One B-rep face of a CAD part: STEP entity #737.
In plain terms, the planar face has unit normal (-1, 0, 0).
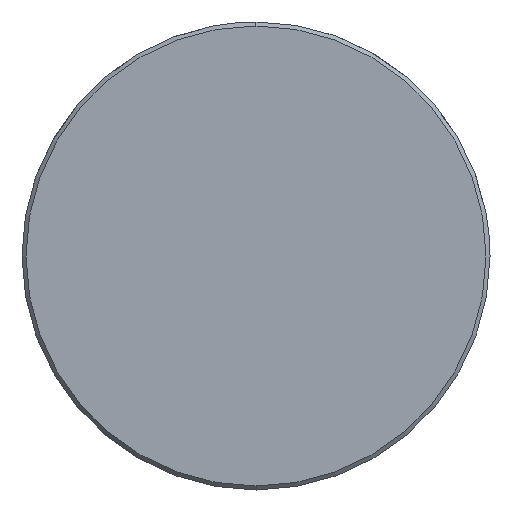
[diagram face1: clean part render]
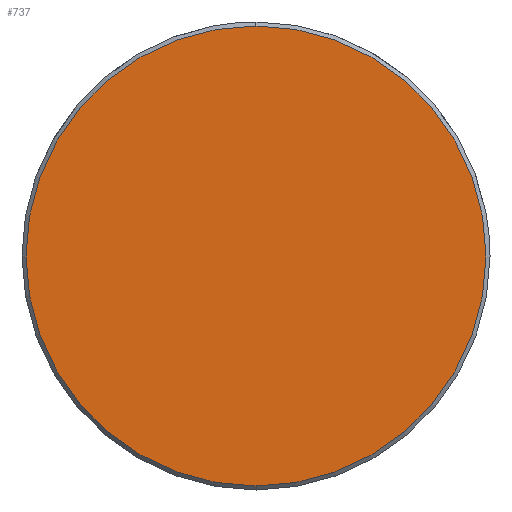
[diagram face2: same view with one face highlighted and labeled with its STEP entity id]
Its self-contained STEP definition (entity closure, numbers rounded to 3 decimals):
#669=CARTESIAN_POINT('Vertex',(0.,0.,-17.2)) ;
#672=CARTESIAN_POINT('Axis2P3D Location',(0.,0.,0.)) ;
#676=CARTESIAN_POINT('Vertex',(0.,17.2,0.)) ;
#679=CARTESIAN_POINT('Axis2P3D Location',(0.,0.,0.)) ;
#683=CARTESIAN_POINT('Vertex',(0.,0.,17.2)) ;
#705=CARTESIAN_POINT('Axis2P3D Location',(0.,0.,0.)) ;
#709=CARTESIAN_POINT('Vertex',(0.,-17.2,0.)) ;
#712=CARTESIAN_POINT('Axis2P3D Location',(0.,0.,0.)) ;
#726=CARTESIAN_POINT('Axis2P3D Location',(0.,0.,0.)) ;
#673=DIRECTION('Axis2P3D Direction',(1.,0.,-0.)) ;
#680=DIRECTION('Axis2P3D Direction',(1.,0.,-0.)) ;
#706=DIRECTION('Axis2P3D Direction',(1.,0.,-0.)) ;
#713=DIRECTION('Axis2P3D Direction',(1.,0.,-0.)) ;
#727=DIRECTION('Axis2P3D Direction',(1.,0.,-0.)) ;
#728=DIRECTION('Axis2P3D XDirection',(-0.,0.,-1.)) ;
#674=AXIS2_PLACEMENT_3D('Circle Axis2P3D',#672,#673,$) ;
#681=AXIS2_PLACEMENT_3D('Circle Axis2P3D',#679,#680,$) ;
#707=AXIS2_PLACEMENT_3D('Circle Axis2P3D',#705,#706,$) ;
#714=AXIS2_PLACEMENT_3D('Circle Axis2P3D',#712,#713,$) ;
#729=AXIS2_PLACEMENT_3D('Plane Axis2P3D',#726,#727,#728) ;
#732=ORIENTED_EDGE('',*,*,#678,.F.) ;
#733=ORIENTED_EDGE('',*,*,#716,.F.) ;
#734=ORIENTED_EDGE('',*,*,#711,.F.) ;
#735=ORIENTED_EDGE('',*,*,#685,.F.) ;
#737=ADVANCED_FACE('549-32X120',(#736),#730,.F.) ;
#675=CIRCLE('generated circle',#674,17.2) ;
#682=CIRCLE('generated circle',#681,17.2) ;
#708=CIRCLE('generated circle',#707,17.2) ;
#715=CIRCLE('generated circle',#714,17.2) ;
#678=EDGE_CURVE('',#670,#677,#675,.T.) ;
#685=EDGE_CURVE('',#677,#684,#682,.T.) ;
#711=EDGE_CURVE('',#684,#710,#708,.T.) ;
#716=EDGE_CURVE('',#710,#670,#715,.T.) ;
#731=EDGE_LOOP('',(#732,#733,#734,#735)) ;
#736=FACE_OUTER_BOUND('',#731,.T.) ;
#730=PLANE('Plane',#729) ;
#670=VERTEX_POINT('',#669) ;
#677=VERTEX_POINT('',#676) ;
#684=VERTEX_POINT('',#683) ;
#710=VERTEX_POINT('',#709) ;
